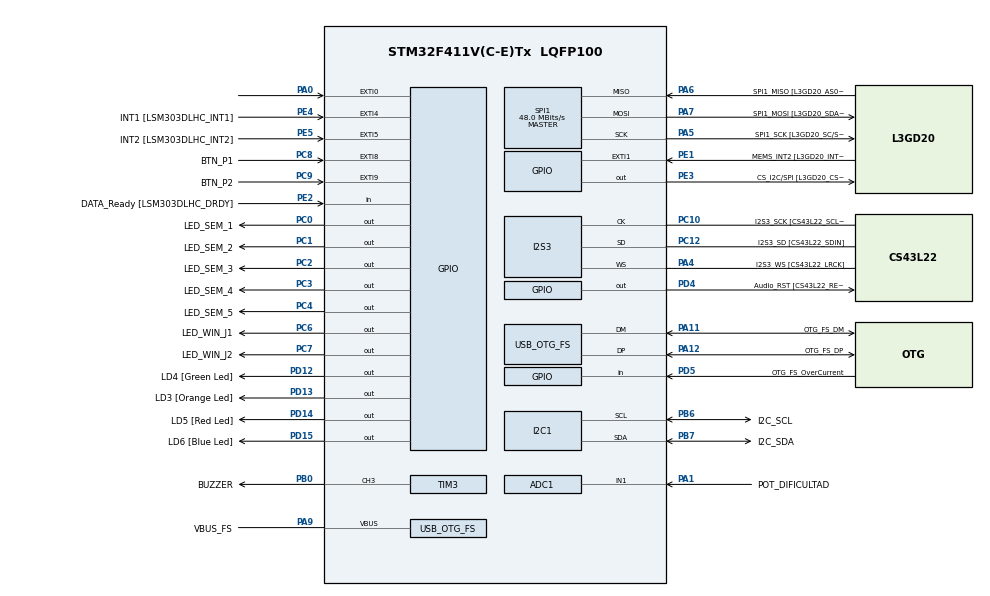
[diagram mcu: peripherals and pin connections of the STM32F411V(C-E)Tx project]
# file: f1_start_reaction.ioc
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ADC1.Channel-0\#ChannelRegularConversion=ADC_CHANNEL_1
ADC1.NbrOfConversionFlag=1
ADC1.Rank-0\#ChannelRegularConversion=1
ADC1.SamplingTime-0\#ChannelRegularConversion=ADC_SAMPLETIME_3CYCLES
ADC1.master=1
I2S3.AudioFreq=I2S_AUDIOFREQ_96K
I2S3.ErrorAudioFreq=0.15 %
I2S3.FullDuplexMode=I2S_FULLDUPLEXMODE_DISABLE
I2S3.Instance=SPI$Index
I2S3.RealAudioFreq=96.153 KHz
I2S3.VirtualMode=I2S_MODE_MASTER
Mcu.Family=STM32F4
Mcu.Name=STM32F411V(C-E)Tx
Mcu.Package=LQFP100
NVIC.EXTI9_5_IRQn=true\:0\:0\:false\:false\:true\:true\:true\:true
NVIC.OTG_FS_IRQn=true\:0\:0\:false\:false\:true\:true\:true\:true
NVIC.PriorityGroup=NVIC_PRIORITYGROUP_0
PA0-WKUP.GPIO_ModeDefaultEXTI=GPIO_MODE_EVT_RISING
PA0-WKUP.Signal=GPXTI0
PA1.GPIO_Label=POT_DIFICULTAD
PA1.Signal=ADCx_IN1
PA10.GPIO_Label=OTG_FS_ID
PA10.Signal=USB_OTG_FS_ID
PA11.GPIO_Label=OTG_FS_DM
PA11.Mode=Host_Only
PA11.Signal=USB_OTG_FS_DM
PA12.GPIO_Label=OTG_FS_DP
PA12.Mode=Host_Only
PA12.Signal=USB_OTG_FS_DP
PA13.GPIO_Label=SWDIO
PA13.Mode=Serial_Wire
PA13.Signal=SYS_JTMS-SWDIO
PA14.GPIO_Label=SWCLK
PA14.Mode=Serial_Wire
PA14.Signal=SYS_JTCK-SWCLK
PA4.GPIO_Label=I2S3_WS [CS43L22_LRCK]
PA4.GPIO_Mode=GPIO_MODE_AF_PP
PA4.GPIO_PuPd=GPIO_NOPULL
PA4.GPIO_Speed=GPIO_SPEED_FREQ_LOW
PA4.Mode=Half_Duplex_Master
PA4.Signal=I2S3_WS
PA5.GPIO_Label=SPI1_SCK [L3GD20_SC/SPC]
PA5.Mode=Full_Duplex_Master
PA5.Signal=SPI1_SCK
PA6.GPIO_Label=SPI1_MISO [L3GD20_AS0/SDO]
PA6.Mode=Full_Duplex_Master
PA6.Signal=SPI1_MISO
PA7.GPIO_Label=SPI1_MOSI [L3GD20_SDA/SDI/SDO]
PA7.Mode=Full_Duplex_Master
PA7.Signal=SPI1_MOSI
PA9.GPIO_Label=VBUS_FS
PA9.Mode=Activate_VBUS
PA9.Signal=USB_OTG_FS_VBUS
PB0.GPIO_Label=BUZZER
PB0.Signal=S_TIM3_CH3
PB10.GPIO_Label=CLK_IN [MP45DT02_CLK]
PB10.Signal=I2S2_CK
PB12.Signal=I2S2_WS
PB3.GPIO_Label=SWO
PB3.Signal=SYS_JTDO-SWO
PB6.GPIO_Label=I2C_SCL
PB6.GPIO_Mode=GPIO_MODE_AF_OD
PB6.GPIO_Pu=GPIO_PULLUP
PB6.GPIO_PuPd=GPIO_NOPULL
PB6.GPIO_Speed=GPIO_SPEED_FREQ_LOW
PB6.Mode=I2C
PB6.Signal=I2C1_SCL
PB7.GPIO_Label=I2C_SDA
PB7.GPIO_Mode=GPIO_MODE_AF_OD
PB7.GPIO_Pu=GPIO_PULLUP
PB7.GPIO_Speed=GPIO_SPEED_FREQ_LOW
PB7.Mode=I2C
PB7.Signal=I2C1_SDA
PC0.GPIO_Label=LED_SEM_1
PC0.Signal=GPIO_Output
PC1.GPIO_Label=LED_SEM_2
PC1.Signal=GPIO_Output
PC10.GPIO_Label=I2S3_SCK [CS43L22_SCLK]
PC10.GPIO_Mode=GPIO_MODE_AF_PP
PC10.GPIO_PuPd=GPIO_NOPULL
PC10.GPIO_Speed=GPIO_SPEED_FREQ_LOW
PC10.Mode=Half_Duplex_Master
PC10.Signal=I2S3_CK
PC12.GPIO_Label=I2S3_SD [CS43L22_SDIN]
PC12.GPIO_Mode=GPIO_MODE_AF_PP
PC12.GPIO_PuPd=GPIO_NOPULL
PC12.GPIO_Speed=GPIO_SPEED_FREQ_LOW
PC12.Mode=Half_Duplex_Master
PC12.Signal=I2S3_SD
PC14-OSC32_IN.GPIO_Label=PC14-OSC32_IN
PC14-OSC32_IN.Mode=LSE-External-Oscillator
PC14-OSC32_IN.Signal=RCC_OSC32_IN
PC15-OSC32_OUT.GPIO_Label=PC15-OSC32_OUT
PC15-OSC32_OUT.Mode=LSE-External-Oscillator
PC15-OSC32_OUT.Signal=RCC_OSC32_OUT
PC2.GPIO_Label=LED_SEM_3
PC2.Signal=GPIO_Output
PC3.GPIO_Label=LED_SEM_4
PC3.Signal=GPIO_Output
PC4.GPIO_Label=LED_SEM_5
PC4.Signal=GPIO_Output
PC6.GPIO_Label=LED_WIN_J1
PC6.Signal=GPIO_Output
PC7.GPIO_Label=LED_WIN_J2
PC7.Signal=GPIO_Output
PC8.GPIO_Label=BTN_P1
PC8.GPIO_PuPd=GPIO_PULLUP
PC8.Signal=GPXTI8
PC9.GPIO_Label=BTN_P2
PC9.GPIO_PuPd=GPIO_PULLUP
PC9.Signal=GPXTI9
PD12.GPIO_Label=LD4 [Green Led]
PD12.GPIO_PuPd=GPIO_NOPULL
PD12.GPIO_Speed=GPIO_SPEED_FREQ_LOW
PD12.Signal=GPIO_Output
PD13.GPIO_Label=LD3 [Orange Led]
PD13.GPIO_PuPd=GPIO_NOPULL
PD13.GPIO_Speed=GPIO_SPEED_FREQ_LOW
PD13.Signal=GPIO_Output
PD14.GPIO_Label=LD5 [Red Led]
PD14.GPIO_PuPd=GPIO_NOPULL
PD14.GPIO_Speed=GPIO_SPEED_FREQ_LOW
PD14.Signal=GPIO_Output
PD15.GPIO_Label=LD6 [Blue Led]
PD15.GPIO_PuPd=GPIO_NOPULL
PD15.GPIO_Speed=GPIO_SPEED_FREQ_LOW
PD15.Signal=GPIO_Output
PD4.GPIO_Label=Audio_RST [CS43L22_RESET]
PD4.Signal=GPIO_Output
PD5.GPIO_Label=OTG_FS_OverCurrent
PD5.Signal=GPIO_Input
PE1.GPIO_Label=MEMS_INT2 [L3GD20_INT2]
PE1.GPIO_ModeDefaultEXTI=GPIO_MODE_EVT_RISING
PE1.Signal=GPXTI1
PE2.GPIO_Label=DATA_Ready [LSM303DLHC_DRDY]
PE2.Signal=GPIO_Input
PE3.GPIO_Label=CS_I2C/SPI [L3GD20_CS_I2C/SPI]
PE3.Signal=GPIO_Output
PE4.GPIO_Label=INT1 [LSM303DLHC_INT1]
PE4.GPIO_ModeDefaultEXTI=GPIO_MODE_EVT_RISING
PE4.Signal=GPXTI4
PE5.GPIO_Label=INT2 [LSM303DLHC_INT2]
PE5.GPIO_ModeDefaultEXTI=GPIO_MODE_EVT_RISING
PE5.Signal=GPXTI5
PH0\ -\ OSC_IN.GPIO_Label=PH0-OSC_IN
PH0\ -\ OSC_IN.Mode=HSE-External-Clock-Source
PH0\ -\ OSC_IN.Signal=RCC_OSC_IN
PH1\ -\ OSC_OUT.GPIO_Label=PH1-OSC_OUT
PH1\ -\ OSC_OUT.Mode=HSE-External-Clock-Source
PH1\ -\ OSC_OUT.Signal=RCC_OSC_OUT
ProjectManager.HeapSize=0x200
ProjectManager.StackSize=0x400
ProjectManager.TargetToolchain=STM32CubeIDE
RCC.48MHZClocksFreq_Value=48000000
RCC.AHBFreq_Value=96000000
RCC.APB1CLKDivider=RCC_HCLK_DIV4
RCC.APB1Freq_Value=24000000
RCC.APB1TimFreq_Value=48000000
RCC.APB2Freq_Value=96000000
RCC.APB2TimFreq_Value=96000000
RCC.CortexFreq_Value=96000000
RCC.HCLKFreq_Value=96000000
RCC.HSE_VALUE=8000000
RCC.HSI_VALUE=16000000
RCC.PLLI2SM=5
RCC.PLLI2SN=200
RCC.PLLM=4
RCC.PLLP=RCC_PLLP_DIV4
RCC.PLLQ=8
RCC.SYSCLKFreq_VALUE=96000000
RCC.SYSCLKSource=RCC_SYSCLKSOURCE_PLLCLK
RCC.VCOOutputFreq_Value=384000000
SH.ADCx_IN1.0=ADC1_IN1,IN1
SH.S_TIM3_CH3.0=TIM3_CH3,PWM Generation3 CH3
SPI1.BaudRatePrescaler=SPI_BAUDRATEPRESCALER_2
SPI1.CalculateBaudRate=48.0 MBits/s
SPI1.Direction=SPI_DIRECTION_2LINES
SPI1.Mode=SPI_MODE_MASTER
SPI1.VirtualType=VM_MASTER
TIM3.Channel-PWM\ Generation3\ CH3=TIM_CHANNEL_3
USB_HOST.USBH_HandleTypeDef=hUsbHostFS
USB_HOST.VirtualModeFS=Cdc
USB_OTG_FS.VirtualMode=Host_Only
USB_OTG_FS.phy_itface=HCD_PHY_EMBEDDED
VP_TIM3_VS_ClockSourceINT.Mode=Internal
VP_USB_HOST_VS_USB_HOST_CDC_FS.Mode=CDC_FS
board=STM32F411E-DISCO

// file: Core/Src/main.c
/* USER CODE BEGIN Header */
/**
  ******************************************************************************
  * @file           : main.c
  * @brief          : Main program body
  ******************************************************************************
  * @attention
  *
  * Copyright (c) 2025 STMicroelectronics.
  * All rights reserved.
  *
  * This software is licensed under terms that can be found in the LICENSE file
  * in the root directory of this software component.
  * If no LICENSE file comes with this software, it is provided AS-IS.
  *
  ******************************************************************************
  */
/* USER CODE END Header */
#include "main.h"
#include "usb_host.h"

/* USER CODE BEGIN Includes */
#include "fsm_f1.h" // Incluimos la librería del juego
/* USER CODE END Includes */

ADC_HandleTypeDef hadc1;

I2C_HandleTypeDef hi2c1;

I2S_HandleTypeDef hi2s3;

SPI_HandleTypeDef hspi1;

TIM_HandleTypeDef htim3;

void SystemClock_Config(void);
static void MX_GPIO_Init(void);
static void MX_I2C1_Init(void);
static void MX_I2S3_Init(void);
static void MX_SPI1_Init(void);
static void MX_ADC1_Init(void);
static void MX_TIM3_Init(void);
void MX_USB_HOST_Process(void);

int main(void)
{

  /* MCU Configuration--------------------------------------------------------*/

  /* Reset of all peripherals, Initializes the Flash interface and the Systick. */
  HAL_Init();

  /* Configure the system clock */
  SystemClock_Config();

  /* Initialize all configured peripherals */
  MX_GPIO_Init();

  MX_I2C1_Init();

  MX_I2S3_Init();
  MX_SPI1_Init();
  MX_USB_HOST_Init();
  MX_ADC1_Init();
  MX_TIM3_Init();

  /* USER CODE BEGIN 2 */

  // inicio variables y pantalla
  iniciar_variables_juego();

  /* USER CODE END 2 */

  /* Infinite loop */
  while (1)
  {
    MX_USB_HOST_Process();

    /* USER CODE BEGIN 3 */

    // bucle del juego
    actualizar_logica_juego();

  }
  /* USER CODE END 3 */
}

void SystemClock_Config(void)
{
  RCC_OscInitTypeDef RCC_OscInitStruct = {0};
  RCC_ClkInitTypeDef RCC_ClkInitStruct = {0};

  /** Configure the main internal regulator output voltage
  */
  __HAL_RCC_PWR_CLK_ENABLE();
  __HAL_PWR_VOLTAGESCALING_CONFIG(PWR_REGULATOR_VOLTAGE_SCALE1);

  /** Initializes the RCC Oscillators according to the specified parameters
  * in the RCC_OscInitTypeDef structure.
  */
  RCC_OscInitStruct.OscillatorType = RCC_OSCILLATORTYPE_HSI;
  RCC_OscInitStruct.HSIState = RCC_HSI_ON;
  RCC_OscInitStruct.HSICalibrationValue = RCC_HSICALIBRATION_DEFAULT;
  RCC_OscInitStruct.PLL.PLLState = RCC_PLL_ON;
  RCC_OscInitStruct.PLL.PLLSource = RCC_PLLSOURCE_HSI;
  RCC_OscInitStruct.PLL.PLLM = 16;
  RCC_OscInitStruct.PLL.PLLN = 336;
  RCC_OscInitStruct.PLL.PLLP = RCC_PLLP_DIV4;
  RCC_OscInitStruct.PLL.PLLQ = 4;
  if (HAL_RCC_OscConfig(&RCC_OscInitStruct) != HAL_OK)
  {
    Error_Handler();
  }

  /** Initializes the CPU, AHB and APB buses clocks
  */
  RCC_ClkInitStruct.ClockType = RCC_CLOCKTYPE_HCLK|RCC_CLOCKTYPE_SYSCLK
                              |RCC_CLOCKTYPE_PCLK1|RCC_CLOCKTYPE_PCLK2;
  RCC_ClkInitStruct.SYSCLKSource = RCC_SYSCLKSOURCE_PLLCLK;
  RCC_ClkInitStruct.AHBCLKDivider = RCC_SYSCLK_DIV1;
  RCC_ClkInitStruct.APB1CLKDivider = RCC_HCLK_DIV4;
  RCC_ClkInitStruct.APB2CLKDivider = RCC_HCLK_DIV1;

  if (HAL_RCC_ClockConfig(&RCC_ClkInitStruct, FLASH_LATENCY_2) != HAL_OK)
  {
    Error_Handler();
  }
}

static void MX_ADC1_Init(void)
{
  ADC_ChannelConfTypeDef sConfig = {0};

  hadc1.Instance = ADC1;
  hadc1.Init.ClockPrescaler = ADC_CLOCK_SYNC_PCLK_DIV4;
  hadc1.Init.Resolution = ADC_RESOLUTION_12B;
  hadc1.Init.ScanConvMode = DISABLE;
  hadc1.Init.ContinuousConvMode = DISABLE;
  hadc1.Init.DiscontinuousConvMode = DISABLE;
  hadc1.Init.ExternalTrigConvEdge = ADC_EXTERNALTRIGCONVEDGE_NONE;
  hadc1.Init.ExternalTrigConv = ADC_SOFTWARE_START;
  hadc1.Init.DataAlign = ADC_DATAALIGN_RIGHT;
  hadc1.Init.NbrOfConversion = 1;
  hadc1.Init.DMAContinuousRequests = DISABLE;
  hadc1.Init.EOCSelection = ADC_EOC_SINGLE_CONV;
  if (HAL_ADC_Init(&hadc1) != HAL_OK)
  {
    Error_Handler();
  }

  sConfig.Channel = ADC_CHANNEL_1;
  sConfig.Rank = 1;
  sConfig.SamplingTime = ADC_SAMPLETIME_3CYCLES;
  if (HAL_ADC_ConfigChannel(&hadc1, &sConfig) != HAL_OK)
  {
    Error_Handler();
  }
}

static void MX_I2C1_Init(void)
{
  hi2c1.Instance = I2C1;
  hi2c1.Init.ClockSpeed = 100000;
  hi2c1.Init.DutyCycle = I2C_DUTYCYCLE_2;
  hi2c1.Init.OwnAddress1 = 0;
  hi2c1.Init.AddressingMode = I2C_ADDRESSINGMODE_7BIT;
  hi2c1.Init.DualAddressMode = I2C_DUALADDRESS_DISABLE;
  hi2c1.Init.OwnAddress2 = 0;
  hi2c1.Init.GeneralCallMode = I2C_GENERALCALL_DISABLE;
  hi2c1.Init.NoStretchMode = I2C_NOSTRETCH_DISABLE;
  if (HAL_I2C_Init(&hi2c1) != HAL_OK)
  {
    Error_Handler();
  }
}

static void MX_I2S3_Init(void)
{
  hi2s3.Instance = SPI3;
  hi2s3.Init.Mode = I2S_MODE_MASTER_TX;
  hi2s3.Init.Standard = I2S_STANDARD_PHILIPS;
  hi2s3.Init.DataFormat = I2S_DATAFORMAT_16B;
  hi2s3.Init.MCLKOutput = I2S_MCLKOUTPUT_DISABLE;
  hi2s3.Init.AudioFreq = I2S_AUDIOFREQ_96K;
  hi2s3.Init.CPOL = I2S_CPOL_LOW;
  hi2s3.Init.ClockSource = I2S_CLOCK_PLL;
  hi2s3.Init.FullDuplexMode = I2S_FULLDUPLEXMODE_DISABLE;
  if (HAL_I2S_Init(&hi2s3) != HAL_OK)
  {
    Error_Handler();
  }
}

static void MX_SPI1_Init(void)
{
  hspi1.Instance = SPI1;
  hspi1.Init.Mode = SPI_MODE_MASTER;
  hspi1.Init.Direction = SPI_DIRECTION_2LINES;
  hspi1.Init.DataSize = SPI_DATASIZE_8BIT;
  hspi1.Init.CLKPolarity = SPI_POLARITY_LOW;
  hspi1.Init.CLKPhase = SPI_PHASE_1EDGE;
  hspi1.Init.NSS = SPI_NSS_SOFT;
  hspi1.Init.BaudRatePrescaler = SPI_BAUDRATEPRESCALER_2;
  hspi1.Init.FirstBit = SPI_FIRSTBIT_MSB;
  hspi1.Init.TIMode = SPI_TIMODE_DISABLE;
  hspi1.Init.CRCCalculation = SPI_CRCCALCULATION_DISABLE;
  hspi1.Init.CRCPolynomial = 10;
  if (HAL_SPI_Init(&hspi1) != HAL_OK)
  {
    Error_Handler();
  }
}

static void MX_TIM3_Init(void)
{
  TIM_ClockConfigTypeDef sClockSourceConfig = {0};
  TIM_MasterConfigTypeDef sMasterConfig = {0};
  TIM_OC_InitTypeDef sConfigOC = {0};

  htim3.Instance = TIM3;
  htim3.Init.Prescaler = 0;
  htim3.Init.CounterMode = TIM_COUNTERMODE_UP;
  htim3.Init.Period = 65535;
  htim3.Init.ClockDivision = TIM_CLOCKDIVISION_DIV1;
  htim3.Init.AutoReloadPreload = TIM_AUTORELOAD_PRELOAD_DISABLE;
  if (HAL_TIM_Base_Init(&htim3) != HAL_OK)
  {
    Error_Handler();
  }
  sClockSourceConfig.ClockSource = TIM_CLOCKSOURCE_INTERNAL;
  if (HAL_TIM_ConfigClockSource(&htim3, &sClockSourceConfig) != HAL_OK)
  {
    Error_Handler();
  }
  if (HAL_TIM_PWM_Init(&htim3) != HAL_OK)
  {
    Error_Handler();
  }
  sMasterConfig.MasterOutputTrigger = TIM_TRGO_RESET;
  sMasterConfig.MasterSlaveMode = TIM_MASTERSLAVEMODE_DISABLE;
  if (HAL_TIMEx_MasterConfigSynchronization(&htim3, &sMasterConfig) != HAL_OK)
  {
    Error_Handler();
  }
  sConfigOC.OCMode = TIM_OCMODE_PWM1;
  sConfigOC.Pulse = 0;
  sConfigOC.OCPolarity = TIM_OCPOLARITY_HIGH;
  sConfigOC.OCFastMode = TIM_OCFAST_DISABLE;
  if (HAL_TIM_PWM_ConfigChannel(&htim3, &sConfigOC, TIM_CHANNEL_3) != HAL_OK)
  {
    Error_Handler();
  }
  HAL_TIM_MspPostInit(&htim3);
}

static void MX_GPIO_Init(void)
{
  GPIO_InitTypeDef GPIO_InitStruct = {0};

  /* GPIO Ports Clock Enable */
  __HAL_RCC_GPIOE_CLK_ENABLE();
  __HAL_RCC_GPIOC_CLK_ENABLE();
  __HAL_RCC_GPIOH_CLK_ENABLE();
  __HAL_RCC_GPIOA_CLK_ENABLE();
  __HAL_RCC_GPIOB_CLK_ENABLE();
  __HAL_RCC_GPIOD_CLK_ENABLE();

  /*Configure GPIO pin Output Level */
  HAL_GPIO_WritePin(CS_I2C_SPI_GPIO_Port, CS_I2C_SPI_Pin, GPIO_PIN_RESET);

  /*Configure GPIO pin Output Level */
  HAL_GPIO_WritePin(GPIOC, LED_SEM_1_Pin|LED_SEM_2_Pin|LED_SEM_3_Pin|LED_SEM_4_Pin
                          |LED_SEM_5_Pin|LED_WIN_J1_Pin|LED_WIN_J2_Pin, GPIO_PIN_RESET);

  /*Configure GPIO pin Output Level */
  HAL_GPIO_WritePin(GPIOD, LD4_Pin|LD3_Pin|LD5_Pin|LD6_Pin
                          |Audio_RST_Pin, GPIO_PIN_RESET);

  /*Configure GPIO pin : DATA_Ready_Pin */
  GPIO_InitStruct.Pin = DATA_Ready_Pin;
  GPIO_InitStruct.Mode = GPIO_MODE_INPUT;
  GPIO_InitStruct.Pull = GPIO_NOPULL;
  HAL_GPIO_Init(DATA_Ready_GPIO_Port, &GPIO_InitStruct);

  /*Configure GPIO pin : CS_I2C_SPI_Pin */
  GPIO_InitStruct.Pin = CS_I2C_SPI_Pin;
  GPIO_InitStruct.Mode = GPIO_MODE_OUTPUT_PP;
  GPIO_InitStruct.Pull = GPIO_NOPULL;
  GPIO_InitStruct.Speed = GPIO_SPEED_FREQ_LOW;
  HAL_GPIO_Init(CS_I2C_SPI_GPIO_Port, &GPIO_InitStruct);

  /*Configure GPIO pins : INT1_Pin INT2_Pin MEMS_INT2_Pin */
  GPIO_InitStruct.Pin = INT1_Pin|INT2_Pin|MEMS_INT2_Pin;
  GPIO_InitStruct.Mode = GPIO_MODE_EVT_RISING;
  GPIO_InitStruct.Pull = GPIO_NOPULL;
  HAL_GPIO_Init(GPIOE, &GPIO_InitStruct);

  /*Configure GPIO pins : LED_SEM_1_Pin LED_SEM_2_Pin LED_SEM_3_Pin LED_SEM_4_Pin
                           LED_SEM_5_Pin LED_WIN_J1_Pin LED_WIN_J2_Pin */
  GPIO_InitStruct.Pin = LED_SEM_1_Pin|LED_SEM_2_Pin|LED_SEM_3_Pin|LED_SEM_4_Pin
                          |LED_SEM_5_Pin|LED_WIN_J1_Pin|LED_WIN_J2_Pin;
  GPIO_InitStruct.Mode = GPIO_MODE_OUTPUT_PP;
  GPIO_InitStruct.Pull = GPIO_NOPULL;
  GPIO_InitStruct.Speed = GPIO_SPEED_FREQ_LOW;
  HAL_GPIO_Init(GPIOC, &GPIO_InitStruct);

  /*Configure GPIO pin : PA0 */
  GPIO_InitStruct.Pin = GPIO_PIN_0;
  GPIO_InitStruct.Mode = GPIO_MODE_EVT_RISING;
  GPIO_InitStruct.Pull = GPIO_NOPULL;
  HAL_GPIO_Init(GPIOA, &GPIO_InitStruct);

  /*Configure GPIO pins : CLK_IN_Pin PB12 */
  GPIO_InitStruct.Pin = CLK_IN_Pin|GPIO_PIN_12;
  GPIO_InitStruct.Mode = GPIO_MODE_AF_PP;
  GPIO_InitStruct.Pull = GPIO_NOPULL;
  GPIO_InitStruct.Speed = GPIO_SPEED_FREQ_LOW;
  GPIO_InitStruct.Alternate = GPIO_AF5_SPI2;
  HAL_GPIO_Init(GPIOB, &GPIO_InitStruct);

  /*Configure GPIO pins : LD4_Pin LD3_Pin LD5_Pin LD6_Pin
                           Audio_RST_Pin */
  GPIO_InitStruct.Pin = LD4_Pin|LD3_Pin|LD5_Pin|LD6_Pin
                          |Audio_RST_Pin;
  GPIO_InitStruct.Mode = GPIO_MODE_OUTPUT_PP;
  GPIO_InitStruct.Pull = GPIO_NOPULL;
  GPIO_InitStruct.Speed = GPIO_SPEED_FREQ_LOW;
  HAL_GPIO_Init(GPIOD, &GPIO_InitStruct);

  /*Configure GPIO pins : BTN_P1_Pin BTN_P2_Pin */
  GPIO_InitStruct.Pin = BTN_P1_Pin|BTN_P2_Pin;
  GPIO_InitStruct.Mode = GPIO_MODE_IT_RISING;
  GPIO_InitStruct.Pull = GPIO_PULLUP;
  HAL_GPIO_Init(GPIOC, &GPIO_InitStruct);

  /*Configure GPIO pin : OTG_FS_OverCurrent_Pin */
  GPIO_InitStruct.Pin = OTG_FS_OverCurrent_Pin;
  GPIO_InitStruct.Mode = GPIO_MODE_INPUT;
  GPIO_InitStruct.Pull = GPIO_NOPULL;
  HAL_GPIO_Init(OTG_FS_OverCurrent_GPIO_Port, &GPIO_InitStruct);

  /* EXTI interrupt init*/
  HAL_NVIC_SetPriority(EXTI9_5_IRQn, 0, 0);
  HAL_NVIC_EnableIRQ(EXTI9_5_IRQn);

}

void Error_Handler(void)
{
  __disable_irq();
  while (1)
  {
  }
}
